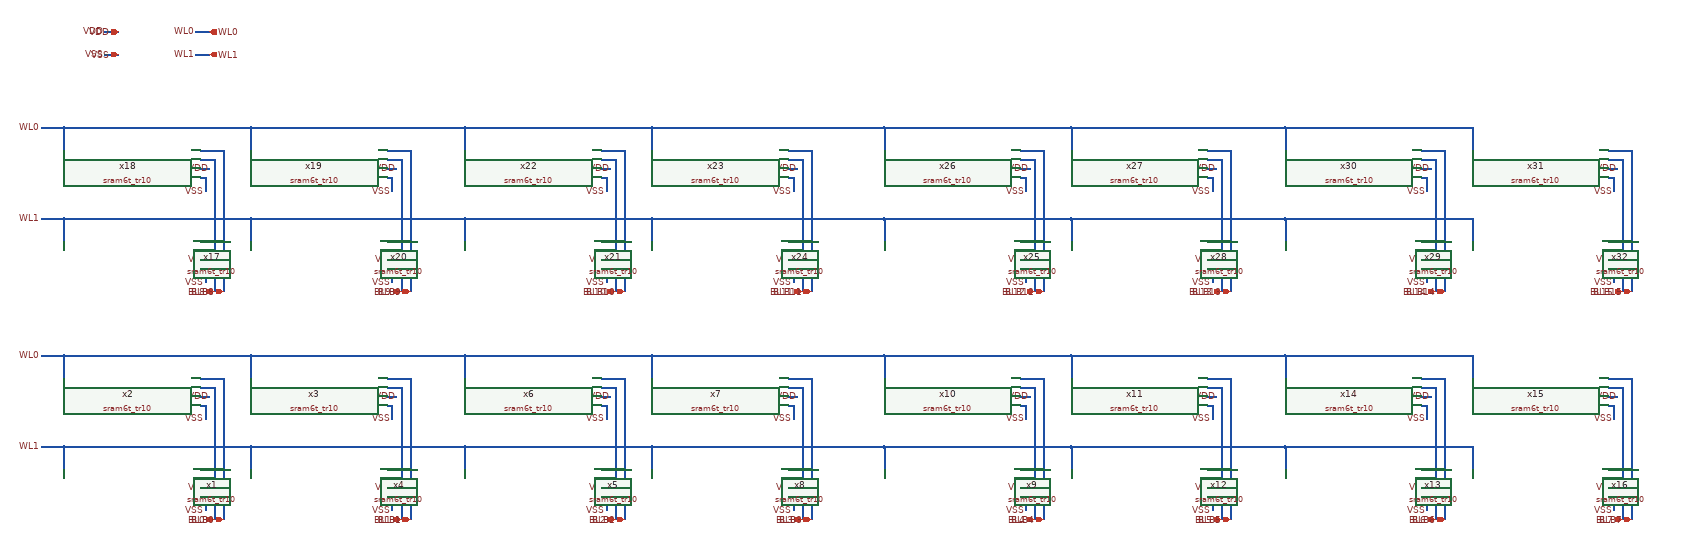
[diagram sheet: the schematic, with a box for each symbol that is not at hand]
v {xschem version=3.4.8RC file_version=1.3}
G {}
K {}
V {}
S {}
F {}
E {}
N 50 -560 50 -510 {lab=WL0}
N 50 -560 460 -560 {lab=WL0}
N 460 -560 460 -510 {lab=WL0}
N 0 -560 50 -560 {lab=WL0}
N 50 -360 50 -310 {lab=WL1}
N 50 -360 460 -360 {lab=WL1}
N 460 -360 460 -310 {lab=WL1}
N -0 -360 50 -360 {lab=WL1}
N 350 -490 380 -490 {lab=BL0}
N 380 -490 380 -200 {lab=BL0}
N 350 -290 380 -290 {lab=BL0}
N 350 -510 400 -510 {lab=BLB0}
N 400 -510 400 -200 {lab=BLB0}
N 350 -310 400 -310 {lab=BLB0}
N 760 -490 790 -490 {lab=BL1}
N 790 -490 790 -200 {lab=BL1}
N 760 -290 790 -290 {lab=BL1}
N 760 -510 810 -510 {lab=BLB1}
N 810 -510 810 -200 {lab=BLB1}
N 760 -310 810 -310 {lab=BLB1}
N 350 -270 370 -270 {lab=VDD}
N 350 -470 370 -470 {lab=VDD}
N 350 -450 360 -450 {lab=VSS}
N 360 -450 360 -420 {lab=VSS}
N 350 -250 360 -250 {lab=VSS}
N 360 -250 360 -220 {lab=VSS}
N 760 -450 770 -450 {lab=VSS}
N 770 -450 770 -420 {lab=VSS}
N 760 -250 770 -250 {lab=VSS}
N 770 -250 770 -220 {lab=VSS}
N 760 -470 780 -470 {lab=VDD}
N 760 -270 780 -270 {lab=VDD}
N 140 -1270 170 -1270 {lab=VDD}
N 140 -1220 170 -1220 {lab=VSS}
N 340 -1270 370 -1270 {lab=WL0}
N 340 -1220 370 -1220 {lab=WL1}
N 930 -560 930 -510 {lab=WL0}
N 930 -560 1340 -560 {lab=WL0}
N 1340 -560 1340 -510 {lab=WL0}
N 880 -560 930 -560 {lab=WL0}
N 930 -360 930 -310 {lab=WL1}
N 930 -360 1340 -360 {lab=WL1}
N 1340 -360 1340 -310 {lab=WL1}
N 880 -360 930 -360 {lab=WL1}
N 1230 -490 1260 -490 {lab=BL2}
N 1260 -490 1260 -200 {lab=BL2}
N 1230 -290 1260 -290 {lab=BL2}
N 1230 -510 1280 -510 {lab=BLB2}
N 1280 -510 1280 -200 {lab=BLB2}
N 1230 -310 1280 -310 {lab=BLB2}
N 1640 -490 1670 -490 {lab=BL3}
N 1670 -490 1670 -200 {lab=BL3}
N 1640 -290 1670 -290 {lab=BL3}
N 1640 -510 1690 -510 {lab=BLB3}
N 1690 -510 1690 -200 {lab=BLB3}
N 1640 -310 1690 -310 {lab=BLB3}
N 1230 -270 1250 -270 {lab=VDD}
N 1230 -470 1250 -470 {lab=VDD}
N 1230 -450 1240 -450 {lab=VSS}
N 1240 -450 1240 -420 {lab=VSS}
N 1230 -250 1240 -250 {lab=VSS}
N 1240 -250 1240 -220 {lab=VSS}
N 1640 -450 1650 -450 {lab=VSS}
N 1650 -450 1650 -420 {lab=VSS}
N 1640 -250 1650 -250 {lab=VSS}
N 1650 -250 1650 -220 {lab=VSS}
N 1640 -470 1660 -470 {lab=VDD}
N 1640 -270 1660 -270 {lab=VDD}
N 460 -560 880 -560 {lab=WL0}
N 460 -360 880 -360 {lab=WL1}
N 1850 -560 1850 -510 {lab=WL0}
N 1850 -560 2260 -560 {lab=WL0}
N 2260 -560 2260 -510 {lab=WL0}
N 1800 -560 1850 -560 {lab=WL0}
N 1850 -360 1850 -310 {lab=WL1}
N 1850 -360 2260 -360 {lab=WL1}
N 2260 -360 2260 -310 {lab=WL1}
N 1800 -360 1850 -360 {lab=WL1}
N 2150 -490 2180 -490 {lab=BL4}
N 2180 -490 2180 -200 {lab=BL4}
N 2150 -290 2180 -290 {lab=BL4}
N 2150 -510 2200 -510 {lab=BLB4}
N 2200 -510 2200 -200 {lab=BLB4}
N 2150 -310 2200 -310 {lab=BLB4}
N 2560 -490 2590 -490 {lab=BL5}
N 2590 -490 2590 -200 {lab=BL5}
N 2560 -290 2590 -290 {lab=BL5}
N 2560 -510 2610 -510 {lab=BLB5}
N 2610 -510 2610 -200 {lab=BLB5}
N 2560 -310 2610 -310 {lab=BLB5}
N 2150 -270 2170 -270 {lab=VDD}
N 2150 -470 2170 -470 {lab=VDD}
N 2150 -450 2160 -450 {lab=VSS}
N 2160 -450 2160 -420 {lab=VSS}
N 2150 -250 2160 -250 {lab=VSS}
N 2160 -250 2160 -220 {lab=VSS}
N 2560 -450 2570 -450 {lab=VSS}
N 2570 -450 2570 -420 {lab=VSS}
N 2560 -250 2570 -250 {lab=VSS}
N 2570 -250 2570 -220 {lab=VSS}
N 2560 -470 2580 -470 {lab=VDD}
N 2560 -270 2580 -270 {lab=VDD}
N 2730 -560 2730 -510 {lab=WL0}
N 2730 -560 3140 -560 {lab=WL0}
N 3140 -560 3140 -510 {lab=WL0}
N 2680 -560 2730 -560 {lab=WL0}
N 2730 -360 2730 -310 {lab=WL1}
N 2730 -360 3140 -360 {lab=WL1}
N 3140 -360 3140 -310 {lab=WL1}
N 2680 -360 2730 -360 {lab=WL1}
N 3030 -490 3060 -490 {lab=BL6}
N 3060 -490 3060 -200 {lab=BL6}
N 3030 -290 3060 -290 {lab=BL6}
N 3030 -510 3080 -510 {lab=BLB6}
N 3080 -510 3080 -200 {lab=BLB6}
N 3030 -310 3080 -310 {lab=BLB6}
N 3440 -490 3470 -490 {lab=BL7}
N 3470 -490 3470 -200 {lab=BL7}
N 3440 -290 3470 -290 {lab=BL7}
N 3440 -510 3490 -510 {lab=BLB7}
N 3490 -510 3490 -200 {lab=BLB7}
N 3440 -310 3490 -310 {lab=BLB7}
N 3030 -270 3050 -270 {lab=VDD}
N 3030 -470 3050 -470 {lab=VDD}
N 3030 -450 3040 -450 {lab=VSS}
N 3040 -450 3040 -420 {lab=VSS}
N 3030 -250 3040 -250 {lab=VSS}
N 3040 -250 3040 -220 {lab=VSS}
N 3440 -450 3450 -450 {lab=VSS}
N 3450 -450 3450 -420 {lab=VSS}
N 3440 -250 3450 -250 {lab=VSS}
N 3450 -250 3450 -220 {lab=VSS}
N 3440 -470 3460 -470 {lab=VDD}
N 3440 -270 3460 -270 {lab=VDD}
N 2260 -560 2680 -560 {lab=WL0}
N 2260 -360 2680 -360 {lab=WL1}
N 1340 -560 1800 -560 {lab=WL0}
N 1340 -360 1800 -360 {lab=WL1}
N 50 -1060 50 -1010 {lab=WL0}
N 50 -1060 460 -1060 {lab=WL0}
N 460 -1060 460 -1010 {lab=WL0}
N 0 -1060 50 -1060 {lab=WL0}
N 50 -860 50 -810 {lab=WL1}
N 50 -860 460 -860 {lab=WL1}
N 460 -860 460 -810 {lab=WL1}
N 0 -860 50 -860 {lab=WL1}
N 350 -990 380 -990 {lab=BL8}
N 380 -990 380 -700 {lab=BL8}
N 350 -790 380 -790 {lab=BL8}
N 350 -1010 400 -1010 {lab=BLB8}
N 400 -1010 400 -700 {lab=BLB8}
N 350 -810 400 -810 {lab=BLB8}
N 760 -990 790 -990 {lab=BL9}
N 790 -990 790 -700 {lab=BL9}
N 760 -790 790 -790 {lab=BL9}
N 760 -1010 810 -1010 {lab=BLB9}
N 810 -1010 810 -700 {lab=BLB9}
N 760 -810 810 -810 {lab=BLB9}
N 350 -770 370 -770 {lab=VDD}
N 350 -970 370 -970 {lab=VDD}
N 350 -950 360 -950 {lab=VSS}
N 360 -950 360 -920 {lab=VSS}
N 350 -750 360 -750 {lab=VSS}
N 360 -750 360 -720 {lab=VSS}
N 760 -950 770 -950 {lab=VSS}
N 770 -950 770 -920 {lab=VSS}
N 760 -750 770 -750 {lab=VSS}
N 770 -750 770 -720 {lab=VSS}
N 760 -970 780 -970 {lab=VDD}
N 760 -770 780 -770 {lab=VDD}
N 930 -1060 930 -1010 {lab=WL0}
N 930 -1060 1340 -1060 {lab=WL0}
N 1340 -1060 1340 -1010 {lab=WL0}
N 880 -1060 930 -1060 {lab=WL0}
N 930 -860 930 -810 {lab=WL1}
N 930 -860 1340 -860 {lab=WL1}
N 1340 -860 1340 -810 {lab=WL1}
N 880 -860 930 -860 {lab=WL1}
N 1230 -990 1260 -990 {lab=BL10}
N 1260 -990 1260 -700 {lab=BL10}
N 1230 -790 1260 -790 {lab=BL10}
N 1230 -1010 1280 -1010 {lab=BLB10}
N 1280 -1010 1280 -700 {lab=BLB10}
N 1230 -810 1280 -810 {lab=BLB10}
N 1640 -990 1670 -990 {lab=BL11}
N 1670 -990 1670 -700 {lab=BL11}
N 1640 -790 1670 -790 {lab=BL11}
N 1640 -1010 1690 -1010 {lab=BLB11}
N 1690 -1010 1690 -700 {lab=BLB11}
N 1640 -810 1690 -810 {lab=BLB11}
N 1230 -770 1250 -770 {lab=VDD}
N 1230 -970 1250 -970 {lab=VDD}
N 1230 -950 1240 -950 {lab=VSS}
N 1240 -950 1240 -920 {lab=VSS}
N 1230 -750 1240 -750 {lab=VSS}
N 1240 -750 1240 -720 {lab=VSS}
N 1640 -950 1650 -950 {lab=VSS}
N 1650 -950 1650 -920 {lab=VSS}
N 1640 -750 1650 -750 {lab=VSS}
N 1650 -750 1650 -720 {lab=VSS}
N 1640 -970 1660 -970 {lab=VDD}
N 1640 -770 1660 -770 {lab=VDD}
N 460 -1060 880 -1060 {lab=WL0}
N 460 -860 880 -860 {lab=WL1}
N 1850 -1060 1850 -1010 {lab=WL0}
N 1850 -1060 2260 -1060 {lab=WL0}
N 2260 -1060 2260 -1010 {lab=WL0}
N 1800 -1060 1850 -1060 {lab=WL0}
N 1850 -860 1850 -810 {lab=WL1}
N 1850 -860 2260 -860 {lab=WL1}
N 2260 -860 2260 -810 {lab=WL1}
N 1800 -860 1850 -860 {lab=WL1}
N 2150 -990 2180 -990 {lab=BL12}
N 2180 -990 2180 -700 {lab=BL12}
N 2150 -790 2180 -790 {lab=BL12}
N 2150 -1010 2200 -1010 {lab=BLB12}
N 2200 -1010 2200 -700 {lab=BLB12}
N 2150 -810 2200 -810 {lab=BLB12}
N 2560 -990 2590 -990 {lab=BL13}
N 2590 -990 2590 -700 {lab=BL13}
N 2560 -790 2590 -790 {lab=BL13}
N 2560 -1010 2610 -1010 {lab=BLB13}
N 2610 -1010 2610 -700 {lab=BLB13}
N 2560 -810 2610 -810 {lab=BLB13}
N 2150 -770 2170 -770 {lab=VDD}
N 2150 -970 2170 -970 {lab=VDD}
N 2150 -950 2160 -950 {lab=VSS}
N 2160 -950 2160 -920 {lab=VSS}
N 2150 -750 2160 -750 {lab=VSS}
N 2160 -750 2160 -720 {lab=VSS}
N 2560 -950 2570 -950 {lab=VSS}
N 2570 -950 2570 -920 {lab=VSS}
N 2560 -750 2570 -750 {lab=VSS}
N 2570 -750 2570 -720 {lab=VSS}
N 2560 -970 2580 -970 {lab=VDD}
N 2560 -770 2580 -770 {lab=VDD}
N 2730 -1060 2730 -1010 {lab=WL0}
N 2730 -1060 3140 -1060 {lab=WL0}
N 3140 -1060 3140 -1010 {lab=WL0}
N 2680 -1060 2730 -1060 {lab=WL0}
N 2730 -860 2730 -810 {lab=WL1}
N 2730 -860 3140 -860 {lab=WL1}
N 3140 -860 3140 -810 {lab=WL1}
N 2680 -860 2730 -860 {lab=WL1}
N 3030 -990 3060 -990 {lab=BL14}
N 3060 -990 3060 -700 {lab=BL14}
N 3030 -790 3060 -790 {lab=BL14}
N 3030 -1010 3080 -1010 {lab=BLB14}
N 3080 -1010 3080 -700 {lab=BLB14}
N 3030 -810 3080 -810 {lab=BLB14}
N 3440 -990 3470 -990 {lab=BL15}
N 3470 -990 3470 -700 {lab=BL15}
N 3440 -790 3470 -790 {lab=BL15}
N 3440 -1010 3490 -1010 {lab=BLB7}
N 3490 -1010 3490 -700 {lab=BLB7}
N 3440 -810 3490 -810 {lab=BLB7}
N 3030 -770 3050 -770 {lab=VDD}
N 3030 -970 3050 -970 {lab=VDD}
N 3030 -950 3040 -950 {lab=VSS}
N 3040 -950 3040 -920 {lab=VSS}
N 3030 -750 3040 -750 {lab=VSS}
N 3040 -750 3040 -720 {lab=VSS}
N 3440 -950 3450 -950 {lab=VSS}
N 3450 -950 3450 -920 {lab=VSS}
N 3440 -750 3450 -750 {lab=VSS}
N 3450 -750 3450 -720 {lab=VSS}
N 3440 -970 3460 -970 {lab=VDD}
N 3440 -770 3460 -770 {lab=VDD}
N 2260 -1060 2680 -1060 {lab=WL0}
N 2260 -860 2680 -860 {lab=WL1}
N 1340 -1060 1800 -1060 {lab=WL0}
N 1340 -860 1800 -860 {lab=WL1}
C {devices/lab_pin.sym} 370 -470 1 1 {name=p1 sig_type=std_logic lab=VDD}
C {devices/lab_pin.sym} 780 -470 1 1 {name=p2 sig_type=std_logic lab=VDD}
C {devices/lab_pin.sym} 370 -270 1 1 {name=p3 sig_type=std_logic lab=VDD}
C {devices/lab_pin.sym} 780 -270 1 1 {name=p4 sig_type=std_logic lab=VDD}
C {devices/lab_pin.sym} 0 -560 0 0 {name=p5 sig_type=std_logic lab=WL0}
C {devices/lab_pin.sym} 0 -360 0 0 {name=p6 sig_type=std_logic lab=WL1}
C {devices/lab_pin.sym} 360 -420 1 1 {name=p11 sig_type=std_logic lab=VSS}
C {devices/lab_pin.sym} 770 -420 1 1 {name=p12 sig_type=std_logic lab=VSS}
C {devices/lab_pin.sym} 360 -220 1 1 {name=p13 sig_type=std_logic lab=VSS}
C {devices/lab_pin.sym} 770 -220 1 1 {name=p14 sig_type=std_logic lab=VSS}
C {devices/iopin.sym} 170 -1270 0 0 {name=p15 lab=VDD}
C {devices/iopin.sym} 170 -1220 0 0 {name=p16 lab=VSS}
C {devices/lab_pin.sym} 140 -1270 0 0 {name=p23 sig_type=std_logic lab=VDD}
C {devices/lab_pin.sym} 140 -1220 0 0 {name=p24 sig_type=std_logic lab=VSS}
C {devices/lab_pin.sym} 340 -1270 0 0 {name=p25 sig_type=std_logic lab=WL0}
C {devices/lab_pin.sym} 340 -1220 0 0 {name=p26 sig_type=std_logic lab=WL1}
C {devices/ipin.sym} 370 -1270 0 1 {name=p17 lab=WL0}
C {devices/ipin.sym} 370 -1220 0 1 {name=p18 lab=WL1}
C {sram6t_tr10.sym} 200 -280 0 0 {name=x1}
C {sram6t_tr10.sym} 200 -480 0 0 {name=x2}
C {sram6t_tr10.sym} 610 -480 0 0 {name=x3}
C {sram6t_tr10.sym} 610 -280 0 0 {name=x4}
C {devices/lab_pin.sym} 1250 -470 1 1 {name=p31 sig_type=std_logic lab=VDD}
C {devices/lab_pin.sym} 1660 -470 1 1 {name=p32 sig_type=std_logic lab=VDD}
C {devices/lab_pin.sym} 1250 -270 1 1 {name=p33 sig_type=std_logic lab=VDD}
C {devices/lab_pin.sym} 1660 -270 1 1 {name=p34 sig_type=std_logic lab=VDD}
C {devices/lab_pin.sym} 1240 -420 1 1 {name=p39 sig_type=std_logic lab=VSS}
C {devices/lab_pin.sym} 1650 -420 1 1 {name=p40 sig_type=std_logic lab=VSS}
C {devices/lab_pin.sym} 1240 -220 1 1 {name=p41 sig_type=std_logic lab=VSS}
C {devices/lab_pin.sym} 1650 -220 1 1 {name=p42 sig_type=std_logic lab=VSS}
C {sram6t_tr10.sym} 1080 -280 0 0 {name=x5}
C {sram6t_tr10.sym} 1080 -480 0 0 {name=x6}
C {sram6t_tr10.sym} 1490 -480 0 0 {name=x7}
C {sram6t_tr10.sym} 1490 -280 0 0 {name=x8}
C {devices/lab_pin.sym} 2170 -470 1 1 {name=p43 sig_type=std_logic lab=VDD}
C {devices/lab_pin.sym} 2580 -470 1 1 {name=p44 sig_type=std_logic lab=VDD}
C {devices/lab_pin.sym} 2170 -270 1 1 {name=p45 sig_type=std_logic lab=VDD}
C {devices/lab_pin.sym} 2580 -270 1 1 {name=p46 sig_type=std_logic lab=VDD}
C {devices/lab_pin.sym} 2160 -420 1 1 {name=p51 sig_type=std_logic lab=VSS}
C {devices/lab_pin.sym} 2570 -420 1 1 {name=p52 sig_type=std_logic lab=VSS}
C {devices/lab_pin.sym} 2160 -220 1 1 {name=p53 sig_type=std_logic lab=VSS}
C {devices/lab_pin.sym} 2570 -220 1 1 {name=p54 sig_type=std_logic lab=VSS}
C {sram6t_tr10.sym} 2000 -280 0 0 {name=x9}
C {sram6t_tr10.sym} 2000 -480 0 0 {name=x10}
C {sram6t_tr10.sym} 2410 -480 0 0 {name=x11}
C {sram6t_tr10.sym} 2410 -280 0 0 {name=x12}
C {devices/lab_pin.sym} 3050 -470 1 1 {name=p55 sig_type=std_logic lab=VDD}
C {devices/lab_pin.sym} 3460 -470 1 1 {name=p56 sig_type=std_logic lab=VDD}
C {devices/lab_pin.sym} 3050 -270 1 1 {name=p57 sig_type=std_logic lab=VDD}
C {devices/lab_pin.sym} 3460 -270 1 1 {name=p58 sig_type=std_logic lab=VDD}
C {devices/lab_pin.sym} 3040 -420 1 1 {name=p63 sig_type=std_logic lab=VSS}
C {devices/lab_pin.sym} 3450 -420 1 1 {name=p64 sig_type=std_logic lab=VSS}
C {devices/lab_pin.sym} 3040 -220 1 1 {name=p65 sig_type=std_logic lab=VSS}
C {devices/lab_pin.sym} 3450 -220 1 1 {name=p66 sig_type=std_logic lab=VSS}
C {sram6t_tr10.sym} 2880 -280 0 0 {name=x13}
C {sram6t_tr10.sym} 2880 -480 0 0 {name=x14}
C {sram6t_tr10.sym} 3290 -480 0 0 {name=x15}
C {sram6t_tr10.sym} 3290 -280 0 0 {name=x16}
C {devices/iopin.sym} 380 -200 1 0 {name=p91 lab=BL0}
C {devices/iopin.sym} 400 -200 1 0 {name=p92 lab=BLB0}
C {devices/iopin.sym} 790 -200 1 0 {name=p7 lab=BL1}
C {devices/iopin.sym} 810 -200 1 0 {name=p8 lab=BLB1}
C {devices/iopin.sym} 1260 -200 1 0 {name=p9 lab=BL2}
C {devices/iopin.sym} 1280 -200 1 0 {name=p10 lab=BLB2}
C {devices/iopin.sym} 1670 -200 1 0 {name=p19 lab=BL3}
C {devices/iopin.sym} 1690 -200 1 0 {name=p20 lab=BLB3}
C {devices/iopin.sym} 2180 -200 1 0 {name=p21 lab=BL4}
C {devices/iopin.sym} 2200 -200 1 0 {name=p22 lab=BLB4}
C {devices/iopin.sym} 2590 -200 1 0 {name=p27 lab=BL5}
C {devices/iopin.sym} 2610 -200 1 0 {name=p28 lab=BLB5}
C {devices/iopin.sym} 3060 -200 1 0 {name=p29 lab=BL6}
C {devices/iopin.sym} 3080 -200 1 0 {name=p30 lab=BLB6}
C {devices/iopin.sym} 3470 -200 1 0 {name=p35 lab=BL7}
C {devices/iopin.sym} 3490 -200 1 0 {name=p36 lab=BLB7}
C {devices/lab_pin.sym} 370 -970 1 1 {name=p37 sig_type=std_logic lab=VDD}
C {devices/lab_pin.sym} 780 -970 1 1 {name=p38 sig_type=std_logic lab=VDD}
C {devices/lab_pin.sym} 370 -770 1 1 {name=p47 sig_type=std_logic lab=VDD}
C {devices/lab_pin.sym} 780 -770 1 1 {name=p48 sig_type=std_logic lab=VDD}
C {devices/lab_pin.sym} 0 -1060 0 0 {name=p49 sig_type=std_logic lab=WL0}
C {devices/lab_pin.sym} 0 -860 0 0 {name=p50 sig_type=std_logic lab=WL1}
C {devices/lab_pin.sym} 360 -920 1 1 {name=p59 sig_type=std_logic lab=VSS}
C {devices/lab_pin.sym} 770 -920 1 1 {name=p60 sig_type=std_logic lab=VSS}
C {devices/lab_pin.sym} 360 -720 1 1 {name=p61 sig_type=std_logic lab=VSS}
C {devices/lab_pin.sym} 770 -720 1 1 {name=p62 sig_type=std_logic lab=VSS}
C {sram6t_tr10.sym} 200 -780 0 0 {name=x17}
C {sram6t_tr10.sym} 200 -980 0 0 {name=x18}
C {sram6t_tr10.sym} 610 -980 0 0 {name=x19}
C {sram6t_tr10.sym} 610 -780 0 0 {name=x20}
C {devices/lab_pin.sym} 1250 -970 1 1 {name=p67 sig_type=std_logic lab=VDD}
C {devices/lab_pin.sym} 1660 -970 1 1 {name=p68 sig_type=std_logic lab=VDD}
C {devices/lab_pin.sym} 1250 -770 1 1 {name=p69 sig_type=std_logic lab=VDD}
C {devices/lab_pin.sym} 1660 -770 1 1 {name=p70 sig_type=std_logic lab=VDD}
C {devices/lab_pin.sym} 1240 -920 1 1 {name=p71 sig_type=std_logic lab=VSS}
C {devices/lab_pin.sym} 1650 -920 1 1 {name=p72 sig_type=std_logic lab=VSS}
C {devices/lab_pin.sym} 1240 -720 1 1 {name=p73 sig_type=std_logic lab=VSS}
C {devices/lab_pin.sym} 1650 -720 1 1 {name=p74 sig_type=std_logic lab=VSS}
C {sram6t_tr10.sym} 1080 -780 0 0 {name=x21}
C {sram6t_tr10.sym} 1080 -980 0 0 {name=x22}
C {sram6t_tr10.sym} 1490 -980 0 0 {name=x23}
C {sram6t_tr10.sym} 1490 -780 0 0 {name=x24}
C {devices/lab_pin.sym} 2170 -970 1 1 {name=p75 sig_type=std_logic lab=VDD}
C {devices/lab_pin.sym} 2580 -970 1 1 {name=p76 sig_type=std_logic lab=VDD}
C {devices/lab_pin.sym} 2170 -770 1 1 {name=p77 sig_type=std_logic lab=VDD}
C {devices/lab_pin.sym} 2580 -770 1 1 {name=p78 sig_type=std_logic lab=VDD}
C {devices/lab_pin.sym} 2160 -920 1 1 {name=p79 sig_type=std_logic lab=VSS}
C {devices/lab_pin.sym} 2570 -920 1 1 {name=p80 sig_type=std_logic lab=VSS}
C {devices/lab_pin.sym} 2160 -720 1 1 {name=p81 sig_type=std_logic lab=VSS}
C {devices/lab_pin.sym} 2570 -720 1 1 {name=p82 sig_type=std_logic lab=VSS}
C {sram6t_tr10.sym} 2000 -780 0 0 {name=x25}
C {sram6t_tr10.sym} 2000 -980 0 0 {name=x26}
C {sram6t_tr10.sym} 2410 -980 0 0 {name=x27}
C {sram6t_tr10.sym} 2410 -780 0 0 {name=x28}
C {devices/lab_pin.sym} 3050 -970 1 1 {name=p83 sig_type=std_logic lab=VDD}
C {devices/lab_pin.sym} 3460 -970 1 1 {name=p84 sig_type=std_logic lab=VDD}
C {devices/lab_pin.sym} 3050 -770 1 1 {name=p85 sig_type=std_logic lab=VDD}
C {devices/lab_pin.sym} 3460 -770 1 1 {name=p86 sig_type=std_logic lab=VDD}
C {devices/lab_pin.sym} 3040 -920 1 1 {name=p87 sig_type=std_logic lab=VSS}
C {devices/lab_pin.sym} 3450 -920 1 1 {name=p88 sig_type=std_logic lab=VSS}
C {devices/lab_pin.sym} 3040 -720 1 1 {name=p89 sig_type=std_logic lab=VSS}
C {devices/lab_pin.sym} 3450 -720 1 1 {name=p90 sig_type=std_logic lab=VSS}
C {sram6t_tr10.sym} 2880 -780 0 0 {name=x29}
C {sram6t_tr10.sym} 2880 -980 0 0 {name=x30}
C {sram6t_tr10.sym} 3290 -980 0 0 {name=x31}
C {sram6t_tr10.sym} 3290 -780 0 0 {name=x32}
C {devices/iopin.sym} 380 -700 1 0 {name=p93 lab=BL8}
C {devices/iopin.sym} 400 -700 1 0 {name=p94 lab=BLB8}
C {devices/iopin.sym} 790 -700 1 0 {name=p95 lab=BL9}
C {devices/iopin.sym} 810 -700 1 0 {name=p96 lab=BLB9}
C {devices/iopin.sym} 1260 -700 1 0 {name=p97 lab=BL10}
C {devices/iopin.sym} 1280 -700 1 0 {name=p98 lab=BLB10}
C {devices/iopin.sym} 1670 -700 1 0 {name=p99 lab=BL11}
C {devices/iopin.sym} 1690 -700 1 0 {name=p100 lab=BLB11}
C {devices/iopin.sym} 2180 -700 1 0 {name=p101 lab=BL12}
C {devices/iopin.sym} 2200 -700 1 0 {name=p102 lab=BLB12}
C {devices/iopin.sym} 2590 -700 1 0 {name=p103 lab=BL13}
C {devices/iopin.sym} 2610 -700 1 0 {name=p104 lab=BLB13}
C {devices/iopin.sym} 3060 -700 1 0 {name=p105 lab=BL14}
C {devices/iopin.sym} 3080 -700 1 0 {name=p106 lab=BLB14}
C {devices/iopin.sym} 3470 -700 1 0 {name=p107 lab=BL15}
C {devices/iopin.sym} 3490 -700 1 0 {name=p108 lab=BLB15}
